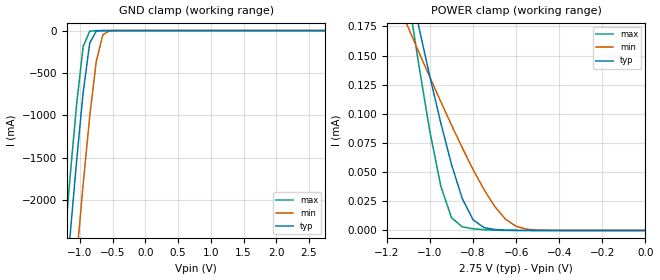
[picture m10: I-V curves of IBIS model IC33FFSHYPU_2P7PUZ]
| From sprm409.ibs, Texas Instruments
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|   Model IC33FFSHYPU_2P7PUZ
[Model]   IC33FFSHYPU_2P7PUZ
Model_type   Input
Polarity   Non-Inverting
Vinl =   0.8250V
Vinh =   1.9250V
C_comp   2.1397pF   2.1767pF   2.7158pF
[Temperature Range]   25.0000   0.1250k   -40.0000
[Voltage Range]   2.7500V   2.5000V   3.0000V
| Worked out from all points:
|   GND clamp passes 1 mA (typ) near -0.66 V on its own axis
|   POWER clamp passes 1 mA (typ) near -1.95 V on its own axis
[GND_clamp]
| voltage   I(typ)   I(min)   I(max)
-2.75V    -17.91A    -19.01A    -17.27A
-1.25V    -3.342A    -4.502A    -2.646A
-1.15V    -2.424A    -3.58A     -1.732A
-1.05V    -1.541A    -2.68A     -871.7mA
-950mV    -732.7mA   -1.814A    -188.7mA
-850mV    -147.8mA   -1.014A    -7.744mA
-750mV    -5.999mA   -364.9mA   -798.5uA
-650mV    -205.8uA   -49.95mA   -59.18uA
-550mV    -9.472uA   -3.226mA   -2.615uA
2.75V     177.4pA    1.86nA     166.1pA
[POWER_clamp]
| voltage   I(typ)   I(min)   I(max)
-2.75V    1.761mA    921.5uA    2.449mA
-1.1V     216.2uA    173.8uA    200.1uA
-1.05V    173.4uA    152.4uA    140.2uA
-1V       131.9uA    131.4uA    84.68uA
-950mV    92.55uA    110.7uA    38.41uA
-900mV    56.73uA    90.48uA    10.94uA
-850mV    27.42uA    70.97uA    3.157uA
-800mV    9.238uA    52.44uA    1.436uA
-700mV    836.6nA    20.75uA    256.9nA
-600mV    104.4nA    3.55uA     18.73nA
-500mV    8.36nA     298.2nA    874.6pA
0V        177.4pA    1.234nA    190.4pA
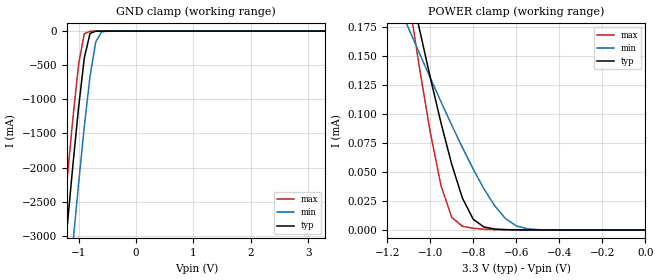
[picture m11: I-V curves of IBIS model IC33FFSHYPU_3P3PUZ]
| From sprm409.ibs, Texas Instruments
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|   Model IC33FFSHYPU_3P3PUZ
[Model]   IC33FFSHYPU_3P3PUZ
Model_type   Input
Polarity   Non-Inverting
Vinl =   0.9900V
Vinh =   2.3100V
C_comp   2.1548pF   2.1455pF   2.3140pF
[Temperature Range]   25.0000   0.1250k   -40.0000
[Voltage Range]   3.3000V   3.0000V   3.6000V
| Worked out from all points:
|   GND clamp passes 1 mA (typ) near -0.69 V on its own axis
|   POWER clamp passes 1 mA (typ) near -1.95 V on its own axis
[GND_clamp]
| voltage   I(typ)   I(min)   I(max)
-3.3V     -23.34A    -24.42A    -22.71A
-1.3V     -3.808A    -4.968A    -3.114A
-1.2V     -2.88A     -4.039A    -2.185A
-1.1V     -1.977A    -3.127A    -1.292A
-1V       -1.123A    -2.241A    -489.8mA
-900mV    -393.5mA   -1.402A    -39.29mA
-800mV    -34.07mA   -660.7mA   -2.405mA
-700mV    -1.067mA   -156.4mA   -232.2uA
-600mV    -42.99uA   -13.12mA   -13.27uA
-400mV    -95.59nA   -45.84uA   -11.78nA
3.3V      227.9pA    3.694nA    215.4pA
[POWER_clamp]
| voltage   I(typ)   I(min)   I(max)
-3.3V     2.287mA    1.176mA    3.216mA
-1.1V     216.2uA    173.8uA    200.1uA
-1.05V    173.4uA    152.4uA    140.2uA
-1V       131.9uA    131.4uA    84.68uA
-950mV    92.55uA    110.7uA    38.41uA
-900mV    56.73uA    90.48uA    10.94uA
-850mV    27.42uA    70.97uA    3.157uA
-800mV    9.238uA    52.44uA    1.437uA
-700mV    836.7nA    20.75uA    257.3nA
-600mV    104.5nA    3.551uA    19.01nA
-500mV    8.433nA    298.9nA    1.094nA
0V        227.9pA    1.675nA    269.3pA
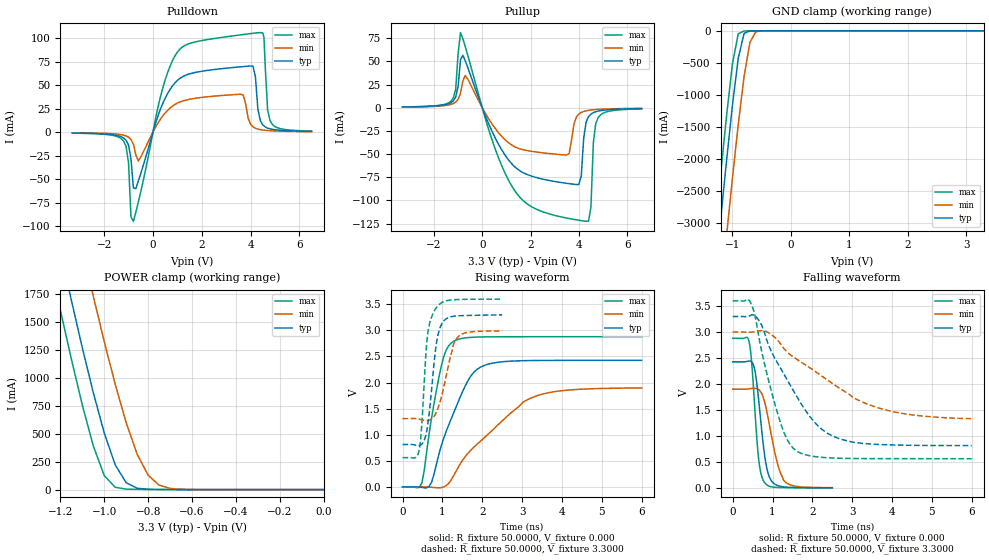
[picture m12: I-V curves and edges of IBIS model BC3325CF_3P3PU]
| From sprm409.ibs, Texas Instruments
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|   Model BC3325CF_3P3PU
[Model]   BC3325CF_3P3PU
Model_type   I/O
Polarity   Non-Inverting
Enable   Active-Low
Vinl =   0.9900V
Vinh =   2.3100V
Vmeas =   1.6500V
Cref =  15.0000pF
Rref = 100.0000M
Vref =  0.000V
C_comp   3.2113000062pf   3.3653001534pf   5.2276998132pf
[Temperature Range]   25.0000   0.1250k   -40.0000
[Voltage Range]   3.3000V   3.0000V   3.6000V
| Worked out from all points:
|   slope of the pulldown table from 0 to 0.495 V, typ, clamps not added: 13.9 ohm
|   slope of the pullup table from 0 to 0.495 V, typ, clamps not added: 16.3 ohm
|   GND clamp passes 1 mA (typ) near -0.68 V on its own axis
|   POWER clamp passes 1 mA (typ) near -0.74 V on its own axis
|   rising waveform, R_fixture 50.0000, V_fixture 0.000: 20-80 % time 710ps typ, 1.48ns min, 380ps max; typ from 0 V to 2.43 V
|   rising waveform, R_fixture 50.0000, V_fixture 3.3000: 20-80 % time 208ps typ, 310ps min, 161ps max; typ from 0.814 V to 3.3 V
|   falling waveform, R_fixture 50.0000, V_fixture 0.000: 20-80 % time 213ps typ, 315ps min, 162ps max; typ from 2.43 V to 0.002 V
|   falling waveform, R_fixture 50.0000, V_fixture 3.3000: 20-80 % time 1.12ns typ, 1.91ns min, 601ps max; typ from 3.3 V to 0.814 V
[Pulldown]
| voltage   I(typ)   I(min)   I(max)
-3.3V     -857uA     -614uA     -1.005mA
-1.2V     -6.162mA   -3.225mA   -9.461mA
-800mV    -59.28mA   -12.78mA   -94.66mA
-600mV    -52.16mA   -30.51mA   -74.44mA
1V        54.91mA    30.86mA    84.97mA
3.6V      69.44mA    40.27mA    103.4mA
4.1V      70.14mA    5.645mA    105mA
4.4V      12.22mA    2.696mA    105.8mA
4.55V     6.668mA    2.131mA    100.8mA
4.7V      4.353mA    1.744mA    23.59mA
4.8V      3.553mA    1.558mA    12.25mA
6.5V      840uA      548uA      1.177mA
|   6.6000   0.8040mA   0.5270mA   1.1170mA
[Pullup]
| voltage   I(typ)   I(min)   I(max)
-3.3V     804uA      687uA      859uA
-1.3V     5.391mA    3.609mA    6.959mA
-900mV    51.9mA     15.62mA    81.15mA
600mV     -35.88mA   -24.51mA   -49.07mA
1.7V      -70.21mA   -45.37mA   -100.4mA
3.5V      -81.59mA   -51.02mA   -119.1mA
4V        -82.9mA    -6.76mA    -121.4mA
4.3V      -15.54mA   -3.316mA   -122.6mA
4.5V      -6.855mA   -2.452mA   -107.1mA
4.6V      -5.293mA   -2.167mA   -37.39mA
4.8V      -3.613mA   -1.755mA   -10.57mA
6.6V      -914uA     -641uA     -1.251mA
[GND_clamp]
| voltage   I(typ)   I(min)   I(max)
-3.3V     -23.4A     -24.49A    -22.76A
-1.3V     -3.859A    -5.036A    -3.154A
-1.2V     -2.93A     -4.106A    -2.224A
-1.1V     -2.025A    -3.192A    -1.329A
-1V       -1.167A    -2.304A    -520.4mA
-900mV    -427mA     -1.461A    -46.18mA
-800mV    -40.82mA   -709.2mA   -2.62mA
-700mV    -1.259mA   -180.2mA   -241.5uA
-600mV    -48.46uA   -16mA      -13.55uA
-400mV    -104.1nA   -53.63uA   -11.97nA
3.3V      273.8pA    876.2nA    249.5pA
[POWER_clamp]
| voltage   I(typ)   I(min)   I(max)
-3.3V     22.53A     23.34A     22.08A
-1.25V    2.586A     3.492A     2.054A
-1.2V     2.135A     3.04A      1.604A
-1.15V    1.695A     2.594A     1.168A
-1.05V    867.5mA    1.733A     390.3mA
-1V       506.5mA    1.325A     124.9mA
-950mV    221.4mA    942.3mA    20.88mA
-900mV    61.07mA    598.5mA    4.539mA
-850mV    12.29mA    317.3mA    2.127mA
-800mV    3.014mA    129mA      1.191mA
-750mV    1.14mA     39.91mA    598.9uA
0V        273.8pA    1.836nA    318pA
[Ramp]
| variable   typ   min   max
dV/dt_r   1.4559/0.7031n   1.1380/1.4643n   1.7275/0.3762n
dV/dt_f   1.4914/1.1133n   1.0008/1.9542n   1.8228/0.5949n
R_load = 50.0000
[Rising Waveform]
R_fixture = 50.0000
V_fixture = 0.000
V_fixture_min = 0.000
V_fixture_max = 0.000
| time   V(typ)   V(min)   V(max)
0s        1.137nV    5.228nV    855.6pV
484.8ps   -8.805mV   1.381mV    77.44mV
727.3ps   88.81mV    -6.171mV   1.317V
969.7ps   784.6mV    -13.66mV   2.308V
1.091ns   1.056V     24.06mV    2.616V
1.273ns   1.401V     201.2mV    2.786V
1.636ns   2.029V     640.2mV    2.861V
1.879ns   2.259V     824.4mV    2.872V
3.212ns   2.422V     1.7V       2.879V
6ns       2.426V     1.897V     2.879V
[Rising Waveform]
R_fixture = 50.0000
V_fixture = 3.3000
V_fixture_min = 3.0000
V_fixture_max = 3.6000
| time   V(typ)   V(min)   V(max)
0s        813.5mV    1.309V     562mV
404ps     794mV      1.3V       658.5mV
479.8ps   817.8mV    1.288V     1.151V
580.8ps   979.3mV    1.273V     2.494V
631.3ps   1.184V     1.272V     2.936V
833.3ps   2.659V     1.41V      3.419V
1.01ns    3.156V     1.833V     3.543V
1.263ns   3.268V     2.68V      3.587V
1.364ns   3.277V     2.85V      3.591V
2.5ns     3.297V     2.99V      3.599V
[Falling Waveform]
R_fixture = 50.0000
V_fixture = 0.000
V_fixture_min = 0.000
V_fixture_max = 0.000
| time   V(typ)   V(min)   V(max)
0s        2.427V     1.901V     2.879V
404ps     2.441V     1.906V     2.839V
479.8ps   2.425V     1.915V     2.389V
580.8ps   2.159V     1.916V     1.228V
681.8ps   1.469V     1.872V     383.8mV
782.8ps   737.4mV    1.704V     122.3mV
934.3ps   186.6mV    1.166V     27.88mV
1.111ns   51.06mV    506.4mV    9.419mV
1.288ns   16.94mV    137.6mV    5.501mV
2.5ns     1.888mV    4.665mV    542.3uV
[Falling Waveform]
R_fixture = 50.0000
V_fixture = 3.3000
V_fixture_min = 3.0000
V_fixture_max = 3.6000
| time   V(typ)   V(min)   V(max)
0s        3.3V       3V         3.6V
484.8ps   3.333V     2.999V     3.506V
727.3ps   3.133V     3.029V     2.632V
1.152ns   2.369V     2.824V     1.374V
1.394ns   2.046V     2.597V     891.5mV
1.636ns   1.724V     2.462V     695.8mV
2.182ns   1.165V     2.183V     592.1mV
2.788ns   923mV      1.867V     568.9mV
4ns       827.2mV    1.472V     562.4mV
6ns       814.3mV    1.332V     562mV
